! (c) 2009  Infineon Technologies AG, Munich
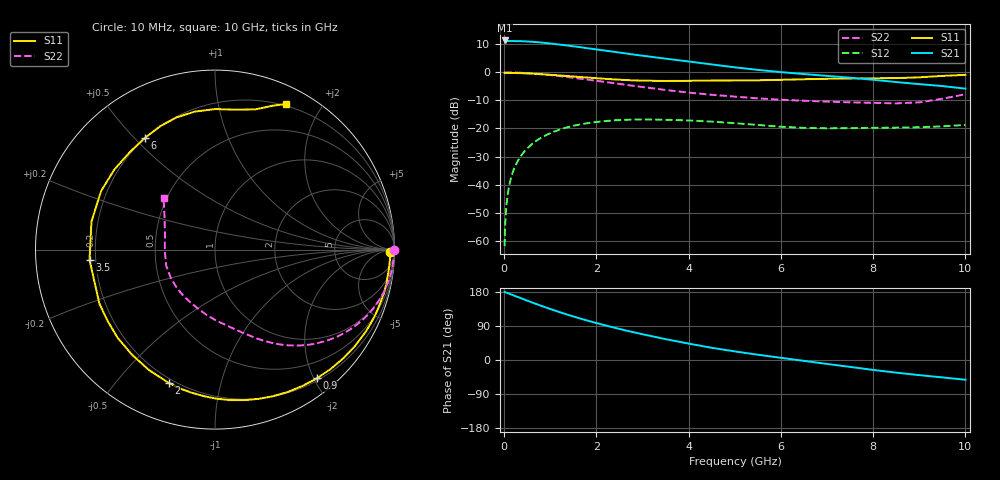
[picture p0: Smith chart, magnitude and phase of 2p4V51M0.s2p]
! Infineon Technologies  Discrete & RF Semiconductors
! BFP420
! VCE =  4.5 V,  IC =  1.0 mA
! Common Emitter S-Parameters:  Nov 2009
# GHz  S  MA  R  50
!  f  S11  S21  S12  S22
! GHz  MAG  ANG  MAG  ANG  MAG  ANG  MAG  ANG
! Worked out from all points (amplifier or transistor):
!   46 points, 10 MHz to 10 GHz, reference 50 ohm
!   highest |S21| = 11.3 dB at 10 MHz (marker M1)
!   |S21| within 3 dB of that: start of sweep to 1.916 GHz
!   unconditionally stable (mu >= 1): 4.413 GHz to end of sweep
!   at 300 MHz: K = 0.04, MSG = 21.3 dB, |S12| = -31.5 dB
!   at 1.7 GHz: K = 0.25, MSG = 13.6 dB, |S12| = -18.4 dB
!   at 10 GHz: K = 1.35, MAG = 2.9 dB, |S12| = -18.7 dB
!   lowest NFmin = 0.53 dB at 900 MHz
!   S11 on the Smith chart (normalised r, x): 10 MHz: 59, -40; 900 MHz: 0.23, -2.05; 2 GHz: 0.18, -0.70; 3.5 GHz: 0.18, -0.04; 6 GHz: 0.20, +0.54; 10 GHz: 0.18, +1.58
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0.01  0.9771 -0.9  3.694 179.4  0.0008 33.8  0.9974 0.0
0.02  0.9736 -1.1  3.564 179.4  0.0018 72.7  0.9959 -0.5
0.05  0.9765 -2.9  3.587 177.6  0.0044 81.4  0.9963 -1.4
0.1  0.9754 -5.8  3.612 175.4  0.0089 84.0  0.996 -3.0
0.2  0.974 -11.5  3.612 170.8  0.0179 81.7  0.9924 -5.9
0.35  0.966 -20.1  3.59 163.8  0.0312 77.4  0.9828 -10.3
0.5  0.9559 -28.8  3.542 156.7  0.0441 72.5  0.9678 -14.6
0.7  0.9368 -40.3  3.456 147.6  0.0605 65.6  0.942 -20.2
0.9  0.915 -51.6  3.332 138.8  0.0754 59.1  0.9104 -25.5
1.3  0.8668 -73.6  3.05 122.5  0.101 46.8  0.8381 -35.2
1.7  0.8183 -94.5  2.769 107.7  0.1201 35.5  0.7617 -43.6
2  0.7862 -109.2  2.555 97.6  0.1303 27.8  0.7071 -49.1
2.6  0.7322 -137.8  2.191 79.0  0.1423 13.9  0.6049 -59.0
3  0.7108 -155.0  1.977 68.0  0.1445 5.9  0.547 -64.8
3.5  0.7014 -175.3  1.752 55.1  0.1429 -2.7  0.4845 -72.1
4  0.7058 167.2  1.559 43.3  0.1388 -9.6  0.4355 -79.7
4.5  0.7137 152.8  1.382 32.2  0.1324 -15.6  0.398 -88.3
5.5  0.7214 131.2  1.105 13.9  0.1154 -22.9  0.3438 -105.5
6  0.7349 122.0  1.008 5.8  0.1074 -23.7  0.3246 -114.9
7  0.7671 106.1  0.864 -10.4  0.1006 -21.8  0.3006 -135.6
8.5  0.7884 81.3  0.671 -33.4  0.1035 -20.5  0.2798 -178.5
10  0.9015 64.1  0.512 -52.1  0.1156 -18.6  0.4063 134.9
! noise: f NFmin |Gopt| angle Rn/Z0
0.9  0.53  0.67  34  0.35
1.8  1.15  0.44  77  0.27
2.4  1.28  0.44  100  0.22
3  1.61  0.45  131  0.15
4  1.9  0.47  -177  0.09
5  2.32  0.44  -133  0.45
6  3.43  0.6  -118  0.25
